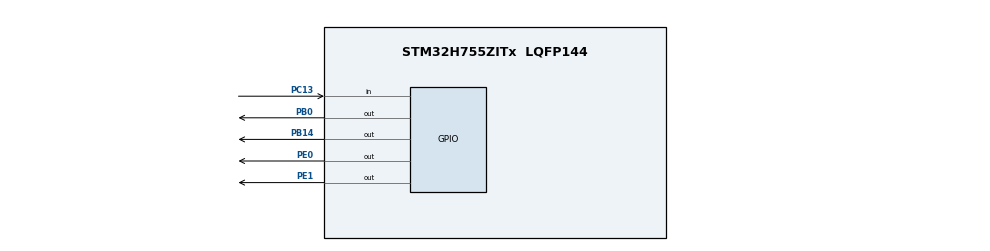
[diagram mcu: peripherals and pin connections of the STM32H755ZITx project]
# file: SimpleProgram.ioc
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CortexM4.IPs=FATFS_M4\:I,FREERTOS_M4\:I,IWDG2\:I,RCC,WWDG2\:I,DMA,BDMA,MDMA,NVIC2\:I,DEBUG,PDM2PCM_M4\:I,PWR,RESMGR_UTILITY,SYS_M4\:I,USB_DEVICE_M4\:I,USB_HOST_M4\:I,CORTEX_M4\:I,GPIO,OPENAMP_M4\:I,VREFBUF,USART3\:I,NUCLEO-H755ZI-Q
CortexM4.Pins=PE0
CortexM7.IPs=FATFS_M7\:I,FREERTOS_M7\:I,IWDG1\:I,RCC\:I,WWDG1\:I,DMA\:I,BDMA\:I,MDMA\:I,NVIC1\:I,USART3,SYS\:I,CORTEX_M7\:I,DEBUG\:I,PDM2PCM_M7\:I,PWR\:I,RESMGR_UTILITY\:I,USB_DEVICE_M7\:I,USB_HOST_M7\:I,GPIO\:I,OPENAMP_M7\:I,VREFBUF\:I,NUCLEO-H755ZI-Q\:I
Mcu.Family=STM32H7
Mcu.Name=STM32H755ZITx
Mcu.Package=LQFP144
NUCLEO-H755ZI-Q.BUTTON=1
NUCLEO-H755ZI-Q.LD1=true
NUCLEO-H755ZI-Q.LD2=true
NUCLEO-H755ZI-Q.LD3=true
NUCLEO-H755ZI-Q.VCP=true
NVIC1.EXTI15_10_IRQn=true\:0\:0\:false\:false\:true\:false\:true\:true
NVIC1.PriorityGroup=NVIC_PRIORITYGROUP_4
NVIC2.HSEM2_IRQn=true\:0\:0\:false\:false\:true\:true\:true\:true
NVIC2.PriorityGroup=NVIC_PRIORITYGROUP_4
PA13\ (JTMS/SWDIO).Mode=Serial_Wire
PA13\ (JTMS/SWDIO).PinAttribute=CortexM7
PA13\ (JTMS/SWDIO).Signal=DEBUG_JTMS-SWDIO
PA14\ (JTCK/SWCLK).Mode=Serial_Wire
PA14\ (JTCK/SWCLK).PinAttribute=CortexM7
PA14\ (JTCK/SWCLK).Signal=DEBUG_JTCK-SWCLK
PB0.Signal=GPIO_Output
PB14.Signal=GPIO_Output
PC13.Signal=GPIO_Input
PE0.PinAttribute=CortexM4
PE0.Signal=GPIO_Output
PE1.Signal=GPIO_Output
ProjectManager.HeapSize=M4-0x8000,M7-0x200
ProjectManager.StackSize=M4-0x400,M7-0x400
ProjectManager.TargetToolchain=STM32CubeIDE
RCC.ADCFreq_Value=75000000
RCC.APB1Freq_Value=98750000
RCC.APB2Freq_Value=98750000
RCC.APB3Freq_Value=98750000
RCC.APB4Freq_Value=98750000
RCC.CortexFreq_Value=395000000
RCC.D1PPRE=RCC_APB3_DIV2
RCC.D2PPRE1=RCC_APB1_DIV2
RCC.D2PPRE2=RCC_APB2_DIV2
RCC.D3PPRE=RCC_APB4_DIV2
RCC.DIVM1=4
RCC.DIVM2=4
RCC.DIVM3=4
RCC.DIVN1=49
RCC.DIVN2=9
RCC.DIVN3=9
RCC.DIVQ1=4
RCC.FLatency-AdvancedSettings=FLASH_LATENCY_1
RCC.HCLKFreq_Value=197500000
RCC.HPRE=RCC_HCLK_DIV2
RCC.LPTIM1CLockSelection=RCC_LPTIM1CLKSOURCE_CLKP
RCC.PLL1_VCI_Range-AdvancedSettings=RCC_PLL1VCIRANGE_0
RCC.PLL2FRACN=3072
RCC.PLL2_VCI_Range-AdvancedSettings=RCC_PLL2VCIRANGE_0
RCC.PLL3FRACN=3072
RCC.PLL3_VCI_Range-AdvancedSettings=RCC_PLL3VCIRANGE_3
RCC.PLL3_VCO_SEL-AdvancedSettings=RCC_PLL3VCOMEDIUM
RCC.PLLFRACN=3072
RCC.SYSCLKFreq_VALUE=395000000
RCC.SYSCLKSource=RCC_SYSCLKSOURCE_PLLCLK
RCC.SupplySource=PWR_DIRECT_SMPS_SUPPLY
RCC.USBFreq_Value=197500000
VP_NUCLEO-H755ZI-Q_VS_BSP_COMMON.Mode=COMMON
VP_SYS_M4_VS_Systick.Mode=SysTick
board=NUCLEO-H755ZI-Q

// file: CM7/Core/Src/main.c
/* USER CODE BEGIN Header */
/**
  ******************************************************************************
  * @file           : main.c
  * @brief          : Main program body
  ******************************************************************************
  * @attention
  *
  * Copyright (c) 2025 STMicroelectronics.
  * All rights reserved.
  *
  * This software is licensed under terms that can be found in the LICENSE file
  * in the root directory of this software component.
  * If no LICENSE file comes with this software, it is provided AS-IS.
  *
  ******************************************************************************
  */
/* USER CODE END Header */
#include "main.h"

/* USER CODE BEGIN PD */

#ifndef HSEM_ID_0
#define HSEM_ID_0 (0U) /* HW semaphore 0*/
#endif

/* USER CODE END PD */

COM_InitTypeDef BspCOMInit;

void SystemClock_Config(void);
static void MX_GPIO_Init(void);

int main(void)
{

/* USER CODE BEGIN Boot_Mode_Sequence_0 */
  int32_t timeout;
/* USER CODE END Boot_Mode_Sequence_0 */

/* USER CODE BEGIN Boot_Mode_Sequence_1 */
  /* Wait until CPU2 boots and enters in stop mode or timeout*/
  timeout = 0xFFFF;
  while((__HAL_RCC_GET_FLAG(RCC_FLAG_D2CKRDY) != RESET) && (timeout-- > 0));
  if ( timeout < 0 )
  {
  Error_Handler();
  }
/* USER CODE END Boot_Mode_Sequence_1 */
  /* MCU Configuration--------------------------------------------------------*/

  /* Reset of all peripherals, Initializes the Flash interface and the Systick. */
  HAL_Init();

  /* Configure the system clock */
  SystemClock_Config();
/* USER CODE BEGIN Boot_Mode_Sequence_2 */
/* When system initialization is finished, Cortex-M7 will release Cortex-M4 by means of
HSEM notification */
/*HW semaphore Clock enable*/
__HAL_RCC_HSEM_CLK_ENABLE();
/*Take HSEM */
HAL_HSEM_FastTake(HSEM_ID_0);
/*Release HSEM in order to notify the CPU2(CM4)*/
HAL_HSEM_Release(HSEM_ID_0,0);
/* wait until CPU2 wakes up from stop mode */
timeout = 0xFFFF;
while((__HAL_RCC_GET_FLAG(RCC_FLAG_D2CKRDY) == RESET) && (timeout-- > 0));
if ( timeout < 0 )
{
Error_Handler();
}
/* USER CODE END Boot_Mode_Sequence_2 */

  /* Initialize all configured peripherals */
  MX_GPIO_Init();

  /* Initialize leds */
  BSP_LED_Init(LED_GREEN);
  BSP_LED_Init(LED_YELLOW);
  BSP_LED_Init(LED_RED);

  /* Initialize USER push-button, will be used to trigger an interrupt each time it's pressed.*/
  BSP_PB_Init(BUTTON_USER, BUTTON_MODE_EXTI);

  /* Initialize COM1 port (115200, 8 bits (7-bit data + 1 stop bit), no parity */
  BspCOMInit.BaudRate   = 115200;
  BspCOMInit.WordLength = COM_WORDLENGTH_8B;
  BspCOMInit.StopBits   = COM_STOPBITS_1;
  BspCOMInit.Parity     = COM_PARITY_NONE;
  BspCOMInit.HwFlowCtl  = COM_HWCONTROL_NONE;
  if (BSP_COM_Init(COM1, &BspCOMInit) != BSP_ERROR_NONE)
  {
    Error_Handler();
  }

  /* Infinite loop */
  /* USER CODE BEGIN WHILE */
  while (1)
  {
	  // Code to change the on-board led color.
	  BSP_LED_On(LED_GREEN);
	  HAL_Delay(300);
	  BSP_LED_Off(LED_GREEN);

	  BSP_LED_On(LED_YELLOW);
	  HAL_Delay(300);
	  BSP_LED_Off(LED_YELLOW);

	  BSP_LED_On(LED_RED);
	  HAL_Delay(300);
	  BSP_LED_Off(LED_RED);

    /* USER CODE END WHILE */

  }
}

void SystemClock_Config(void)
{
  RCC_OscInitTypeDef RCC_OscInitStruct = {0};
  RCC_ClkInitTypeDef RCC_ClkInitStruct = {0};

  /** Supply configuration update enable
  */
  HAL_PWREx_ConfigSupply(PWR_DIRECT_SMPS_SUPPLY);

  /** Configure the main internal regulator output voltage
  */
  __HAL_PWR_VOLTAGESCALING_CONFIG(PWR_REGULATOR_VOLTAGE_SCALE1);

  while(!__HAL_PWR_GET_FLAG(PWR_FLAG_VOSRDY)) {}

  /** Initializes the RCC Oscillators according to the specified parameters
  * in the RCC_OscInitTypeDef structure.
  */
  RCC_OscInitStruct.OscillatorType = RCC_OSCILLATORTYPE_HSI;
  RCC_OscInitStruct.HSIState = RCC_HSI_DIV1;
  RCC_OscInitStruct.HSICalibrationValue = RCC_HSICALIBRATION_DEFAULT;
  RCC_OscInitStruct.PLL.PLLState = RCC_PLL_ON;
  RCC_OscInitStruct.PLL.PLLSource = RCC_PLLSOURCE_HSI;
  RCC_OscInitStruct.PLL.PLLM = 4;
  RCC_OscInitStruct.PLL.PLLN = 50;
  RCC_OscInitStruct.PLL.PLLP = 2;
  RCC_OscInitStruct.PLL.PLLQ = 4;
  RCC_OscInitStruct.PLL.PLLR = 2;
  RCC_OscInitStruct.PLL.PLLRGE = RCC_PLL1VCIRANGE_3;
  RCC_OscInitStruct.PLL.PLLVCOSEL = RCC_PLL1VCOWIDE;
  RCC_OscInitStruct.PLL.PLLFRACN = 0;
  if (HAL_RCC_OscConfig(&RCC_OscInitStruct) != HAL_OK)
  {
    Error_Handler();
  }

  /** Initializes the CPU, AHB and APB buses clocks
  */
  RCC_ClkInitStruct.ClockType = RCC_CLOCKTYPE_HCLK|RCC_CLOCKTYPE_SYSCLK
                              |RCC_CLOCKTYPE_PCLK1|RCC_CLOCKTYPE_PCLK2
                              |RCC_CLOCKTYPE_D3PCLK1|RCC_CLOCKTYPE_D1PCLK1;
  RCC_ClkInitStruct.SYSCLKSource = RCC_SYSCLKSOURCE_PLLCLK;
  RCC_ClkInitStruct.SYSCLKDivider = RCC_SYSCLK_DIV1;
  RCC_ClkInitStruct.AHBCLKDivider = RCC_HCLK_DIV2;
  RCC_ClkInitStruct.APB3CLKDivider = RCC_APB3_DIV2;
  RCC_ClkInitStruct.APB1CLKDivider = RCC_APB1_DIV2;
  RCC_ClkInitStruct.APB2CLKDivider = RCC_APB2_DIV2;
  RCC_ClkInitStruct.APB4CLKDivider = RCC_APB4_DIV2;

  if (HAL_RCC_ClockConfig(&RCC_ClkInitStruct, FLASH_LATENCY_2) != HAL_OK)
  {
    Error_Handler();
  }
}

static void MX_GPIO_Init(void)
{

  /* GPIO Ports Clock Enable */
  __HAL_RCC_GPIOA_CLK_ENABLE();

}

/* USER CODE BEGIN 4 */

BSP_PB_Callback(Button_TypeDef Button){
	// Code for the interrupt from the user button goes here

	  BSP_LED_On(LED_GREEN);
	  BSP_LED_On(LED_YELLOW);
	  BSP_LED_On(LED_RED);
}

/* USER CODE END 4 */

void Error_Handler(void)
{
  __disable_irq();
  while (1)
  {
  }
}
